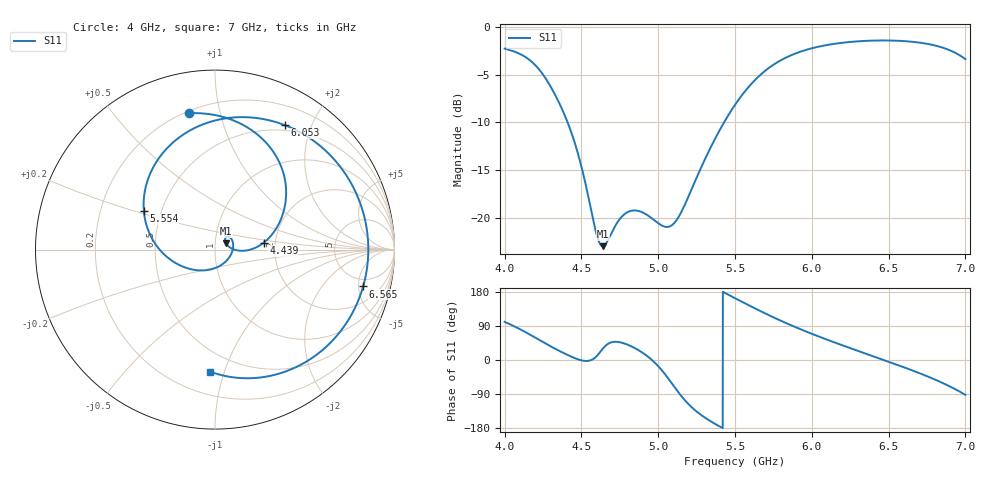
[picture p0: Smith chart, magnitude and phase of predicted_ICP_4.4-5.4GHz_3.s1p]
! ICP-predicted S11, target 4.400-5.400 GHz at -10 dB. Complex ensemble mean (passive and causal);
! its |S11| can differ slightly from the dB-domain mean reported in designs.csv.
!  Air_gap = 2.18mm
!  W_Patch = 12.82mm
!  L_Patch = 18.84mm
!  Sx = 0.65mm
!  Sy = 3.98mm
!  W_Patch1 = 14.35mm
!  WS = 1.14mm
!  Curve_Amp1 = 2.74mm
!  Extra = 5.1mm
# GHz S MA R 50
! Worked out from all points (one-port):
!   3001 points, 4 GHz to 7 GHz, reference 50 ohm
!   lowest |S11| = -23.0 dB at 4.639 GHz (marker M1), VSWR 1.15, Z = 56.4 + j3.97 ohm
!   |S11| at or under -10 dB: 4.41 GHz to 5.428 GHz (1.018 GHz wide, 20.7 % of centre)
!   S11 on the Smith chart (normalised r, x): 4 GHz: 0.21, +0.81; 4.439 GHz: 1.73, +0.14; 5.554 GHz: 0.40, +0.21; 6.053 GHz: 0.43, +1.62; 6.565 GHz: 3.80, -5.65; 7 GHz: 0.35, -0.90
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4  0.7737 100.6
4.111  0.7176 79.0
4.218  0.6102 54.7
4.29  0.5037 38.1
4.375  0.3702 20.2
4.439  0.2733 8.0
4.513  0.1681 -2.0
4.599  0.08138 10.1
4.639  0.07068 29.7
4.75  0.09826 46.9
4.844  0.1089 32.2
4.959  0.09895 0.1
5.056  0.08916 -43.7
5.125  0.09834 -81.9
5.321  0.2162 -156.5
5.5  0.3916 163.0
5.554  0.4498 151.7
5.699  0.5937 122.4
5.875  0.7193 90.0
6.053  0.795 60.8
6.25  0.8389 31.3
6.41  0.8531 8.4
6.565  0.8506 -14.0
6.625  0.8447 -22.9
6.732  0.825 -39.7
6.84  0.7884 -58.4
6.922  0.7437 -74.5
7  0.681 -92.1
